VERSION 5.7 ;
  NOWIREEXTENSIONATPIN ON ;
  DIVIDERCHAR "/" ;
  BUSBITCHARS "[]" ;
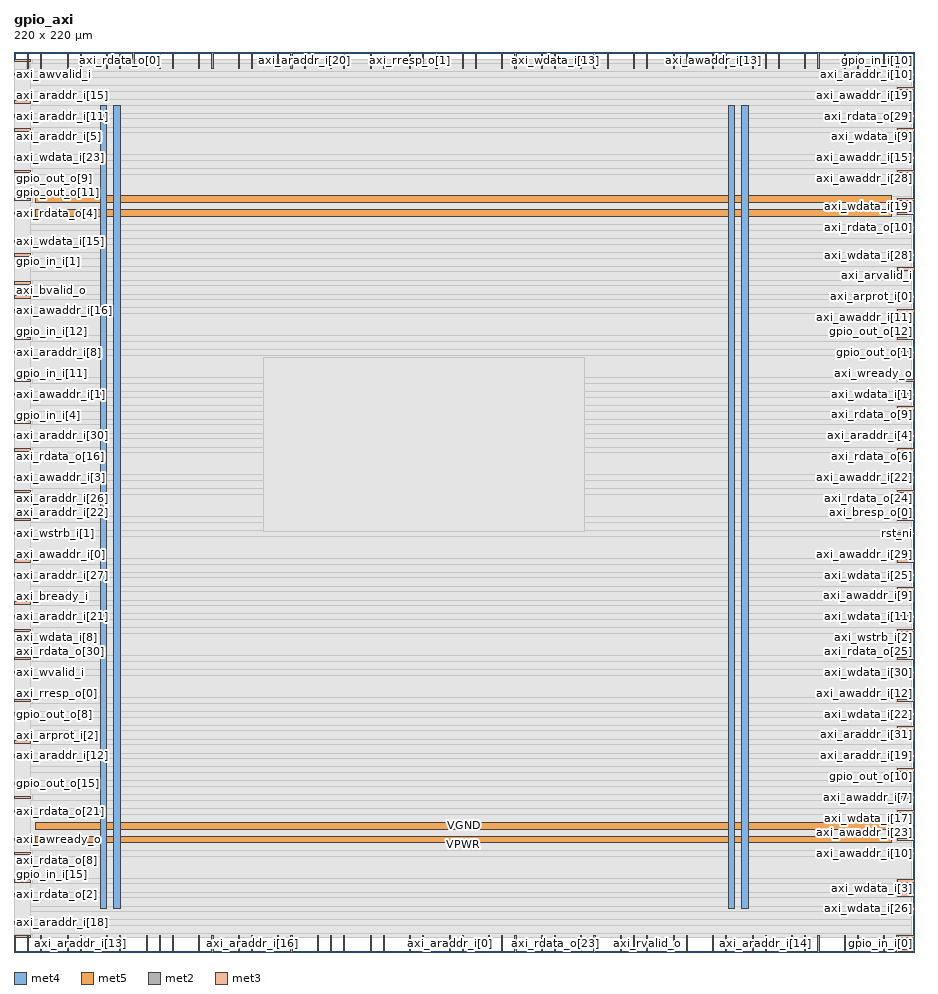
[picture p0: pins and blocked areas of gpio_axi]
MACRO gpio_axi
  CLASS BLOCK ;
  FOREIGN gpio_axi ;
  ORIGIN 0.000 0.000 ;
  SIZE 220.000 BY 220.000 ;
  PIN VGND
    DIRECTION INOUT ;
    USE GROUND ;
    PORT
      LAYER met4 ;
        RECT 24.340 10.640 25.940 206.960 ;
    END
    PORT
      LAYER met4 ;
        RECT 177.940 10.640 179.540 206.960 ;
    END
    PORT
      LAYER met5 ;
        RECT 5.280 30.030 214.600 31.630 ;
    END
    PORT
      LAYER met5 ;
        RECT 5.280 183.210 214.600 184.810 ;
    END
  END VGND
  PIN VPWR
    DIRECTION INOUT ;
    USE POWER ;
    PORT
      LAYER met4 ;
        RECT 21.040 10.640 22.640 206.960 ;
    END
    PORT
      LAYER met4 ;
        RECT 174.640 10.640 176.240 206.960 ;
    END
    PORT
      LAYER met5 ;
        RECT 5.280 26.730 214.600 28.330 ;
    END
    PORT
      LAYER met5 ;
        RECT 5.280 179.910 214.600 181.510 ;
    END
  END VPWR
  PIN axi_araddr_i[0]
    DIRECTION INPUT ;
    USE SIGNAL ;
    PORT
      LAYER met2 ;
        RECT 106.350 0.000 106.630 4.000 ;
    END
  END axi_araddr_i[0]
  PIN axi_araddr_i[10]
    DIRECTION INPUT ;
    USE SIGNAL ;
    PORT
      LAYER met3 ;
        RECT 216.000 214.240 220.000 214.840 ;
    END
  END axi_araddr_i[10]
  PIN axi_araddr_i[11]
    DIRECTION INPUT ;
    USE SIGNAL ;
    PORT
      LAYER met3 ;
        RECT 0.000 204.040 4.000 204.640 ;
    END
  END axi_araddr_i[11]
  PIN axi_araddr_i[12]
    DIRECTION INPUT ;
    USE SIGNAL ;
    PORT
      LAYER met3 ;
        RECT 0.000 47.640 4.000 48.240 ;
    END
  END axi_araddr_i[12]
  PIN axi_araddr_i[13]
    DIRECTION INPUT ;
    USE SIGNAL ;
    PORT
      LAYER met2 ;
        RECT 16.190 0.000 16.470 4.000 ;
    END
  END axi_araddr_i[13]
  PIN axi_araddr_i[14]
    DIRECTION INPUT ;
    USE SIGNAL ;
    PORT
      LAYER met2 ;
        RECT 183.630 0.000 183.910 4.000 ;
    END
  END axi_araddr_i[14]
  PIN axi_araddr_i[15]
    DIRECTION INPUT ;
    USE SIGNAL ;
    PORT
      LAYER met3 ;
        RECT 0.000 207.440 4.000 208.040 ;
    END
  END axi_araddr_i[15]
  PIN axi_araddr_i[16]
    DIRECTION INPUT ;
    USE SIGNAL ;
    PORT
      LAYER met2 ;
        RECT 58.050 0.000 58.330 4.000 ;
    END
  END axi_araddr_i[16]
  PIN axi_araddr_i[17]
    DIRECTION INPUT ;
    USE SIGNAL ;
    PORT
      LAYER met3 ;
        RECT 216.000 17.040 220.000 17.640 ;
    END
  END axi_araddr_i[17]
  PIN axi_araddr_i[18]
    DIRECTION INPUT ;
    USE SIGNAL ;
    PORT
      LAYER met3 ;
        RECT 0.000 6.840 4.000 7.440 ;
    END
  END axi_araddr_i[18]
  PIN axi_araddr_i[19]
    DIRECTION INPUT ;
    USE SIGNAL ;
    PORT
      LAYER met3 ;
        RECT 216.000 47.640 220.000 48.240 ;
    END
  END axi_araddr_i[19]
  PIN axi_araddr_i[1]
    DIRECTION INPUT ;
    USE SIGNAL ;
    PORT
      LAYER met2 ;
        RECT 193.290 0.000 193.570 4.000 ;
    END
  END axi_araddr_i[1]
  PIN axi_araddr_i[20]
    DIRECTION INPUT ;
    USE SIGNAL ;
    PORT
      LAYER met2 ;
        RECT 70.930 216.000 71.210 220.000 ;
    END
  END axi_araddr_i[20]
  PIN axi_araddr_i[21]
    DIRECTION INPUT ;
    USE SIGNAL ;
    PORT
      LAYER met3 ;
        RECT 0.000 81.640 4.000 82.240 ;
    END
  END axi_araddr_i[21]
  PIN axi_araddr_i[22]
    DIRECTION INPUT ;
    USE SIGNAL ;
    PORT
      LAYER met3 ;
        RECT 0.000 105.440 4.000 106.040 ;
    END
  END axi_araddr_i[22]
  PIN axi_araddr_i[23]
    DIRECTION INPUT ;
    USE SIGNAL ;
    PORT
      LAYER met2 ;
        RECT 122.450 216.000 122.730 220.000 ;
    END
  END axi_araddr_i[23]
  PIN axi_araddr_i[24]
    DIRECTION INPUT ;
    USE SIGNAL ;
    PORT
      LAYER met2 ;
        RECT 48.390 0.000 48.670 4.000 ;
    END
  END axi_araddr_i[24]
  PIN axi_araddr_i[25]
    DIRECTION INPUT ;
    USE SIGNAL ;
    PORT
      LAYER met2 ;
        RECT 64.490 216.000 64.770 220.000 ;
    END
  END axi_araddr_i[25]
  PIN axi_araddr_i[26]
    DIRECTION INPUT ;
    USE SIGNAL ;
    PORT
      LAYER met3 ;
        RECT 0.000 112.240 4.000 112.840 ;
    END
  END axi_araddr_i[26]
  PIN axi_araddr_i[27]
    DIRECTION INPUT ;
    USE SIGNAL ;
    PORT
      LAYER met3 ;
        RECT 0.000 91.840 4.000 92.440 ;
    END
  END axi_araddr_i[27]
  PIN axi_araddr_i[28]
    DIRECTION INPUT ;
    USE SIGNAL ;
    PORT
      LAYER met2 ;
        RECT 141.770 0.000 142.050 4.000 ;
    END
  END axi_araddr_i[28]
  PIN axi_araddr_i[29]
    DIRECTION INPUT ;
    USE SIGNAL ;
    PORT
      LAYER met2 ;
        RECT 196.510 216.000 196.790 220.000 ;
    END
  END axi_araddr_i[29]
  PIN axi_araddr_i[2]
    DIRECTION INPUT ;
    USE SIGNAL ;
    ANTENNAGATEAREA 0.196500 ;
    PORT
      LAYER met2 ;
        RECT 119.230 216.000 119.510 220.000 ;
    END
  END axi_araddr_i[2]
  PIN axi_araddr_i[30]
    DIRECTION INPUT ;
    USE SIGNAL ;
    PORT
      LAYER met3 ;
        RECT 0.000 125.840 4.000 126.440 ;
    END
  END axi_araddr_i[30]
  PIN axi_araddr_i[31]
    DIRECTION INPUT ;
    USE SIGNAL ;
    PORT
      LAYER met3 ;
        RECT 216.000 54.440 220.000 55.040 ;
    END
  END axi_araddr_i[31]
  PIN axi_araddr_i[3]
    DIRECTION INPUT ;
    USE SIGNAL ;
    ANTENNAGATEAREA 0.213000 ;
    PORT
      LAYER met2 ;
        RECT 45.170 216.000 45.450 220.000 ;
    END
  END axi_araddr_i[3]
  PIN axi_araddr_i[4]
    DIRECTION INPUT ;
    USE SIGNAL ;
    PORT
      LAYER met3 ;
        RECT 216.000 125.840 220.000 126.440 ;
    END
  END axi_araddr_i[4]
  PIN axi_araddr_i[5]
    DIRECTION INPUT ;
    USE SIGNAL ;
    PORT
      LAYER met3 ;
        RECT 0.000 200.640 4.000 201.240 ;
    END
  END axi_araddr_i[5]
  PIN axi_araddr_i[6]
    DIRECTION INPUT ;
    USE SIGNAL ;
    PORT
      LAYER met2 ;
        RECT 193.290 216.000 193.570 220.000 ;
    END
  END axi_araddr_i[6]
  PIN axi_araddr_i[7]
    DIRECTION INPUT ;
    USE SIGNAL ;
    PORT
      LAYER met2 ;
        RECT 138.550 216.000 138.830 220.000 ;
    END
  END axi_araddr_i[7]
  PIN axi_araddr_i[8]
    DIRECTION INPUT ;
    USE SIGNAL ;
    PORT
      LAYER met3 ;
        RECT 0.000 146.240 4.000 146.840 ;
    END
  END axi_araddr_i[8]
  PIN axi_araddr_i[9]
    DIRECTION INPUT ;
    USE SIGNAL ;
    PORT
      LAYER met3 ;
        RECT 216.000 183.640 220.000 184.240 ;
    END
  END axi_araddr_i[9]
  PIN axi_arprot_i[0]
    DIRECTION INPUT ;
    USE SIGNAL ;
    PORT
      LAYER met3 ;
        RECT 216.000 159.840 220.000 160.440 ;
    END
  END axi_arprot_i[0]
  PIN axi_arprot_i[1]
    DIRECTION INPUT ;
    USE SIGNAL ;
    PORT
      LAYER met2 ;
        RECT 206.170 0.000 206.450 4.000 ;
    END
  END axi_arprot_i[1]
  PIN axi_arprot_i[2]
    DIRECTION INPUT ;
    USE SIGNAL ;
    PORT
      LAYER met3 ;
        RECT 0.000 51.040 4.000 51.640 ;
    END
  END axi_arprot_i[2]
  PIN axi_arready_o
    DIRECTION OUTPUT TRISTATE ;
    USE SIGNAL ;
    ANTENNADIFFAREA 0.795200 ;
    PORT
      LAYER met2 ;
        RECT 67.710 216.000 67.990 220.000 ;
    END
  END axi_arready_o
  PIN axi_arvalid_i
    DIRECTION INPUT ;
    USE SIGNAL ;
    ANTENNAGATEAREA 0.196500 ;
    PORT
      LAYER met3 ;
        RECT 216.000 166.640 220.000 167.240 ;
    END
  END axi_arvalid_i
  PIN axi_awaddr_i[0]
    DIRECTION INPUT ;
    USE SIGNAL ;
    PORT
      LAYER met3 ;
        RECT 0.000 95.240 4.000 95.840 ;
    END
  END axi_awaddr_i[0]
  PIN axi_awaddr_i[10]
    DIRECTION INPUT ;
    USE SIGNAL ;
    PORT
      LAYER met3 ;
        RECT 216.000 23.840 220.000 24.440 ;
    END
  END axi_awaddr_i[10]
  PIN axi_awaddr_i[11]
    DIRECTION INPUT ;
    USE SIGNAL ;
    PORT
      LAYER met3 ;
        RECT 216.000 156.440 220.000 157.040 ;
    END
  END axi_awaddr_i[11]
  PIN axi_awaddr_i[12]
    DIRECTION INPUT ;
    USE SIGNAL ;
    PORT
      LAYER met3 ;
        RECT 216.000 61.240 220.000 61.840 ;
    END
  END axi_awaddr_i[12]
  PIN axi_awaddr_i[13]
    DIRECTION INPUT ;
    USE SIGNAL ;
    PORT
      LAYER met2 ;
        RECT 170.750 216.000 171.030 220.000 ;
    END
  END axi_awaddr_i[13]
  PIN axi_awaddr_i[14]
    DIRECTION INPUT ;
    USE SIGNAL ;
    PORT
      LAYER met2 ;
        RECT 164.310 216.000 164.590 220.000 ;
    END
  END axi_awaddr_i[14]
  PIN axi_awaddr_i[15]
    DIRECTION INPUT ;
    USE SIGNAL ;
    PORT
      LAYER met3 ;
        RECT 216.000 193.840 220.000 194.440 ;
    END
  END axi_awaddr_i[15]
  PIN axi_awaddr_i[16]
    DIRECTION INPUT ;
    USE SIGNAL ;
    PORT
      LAYER met3 ;
        RECT 0.000 156.440 4.000 157.040 ;
    END
  END axi_awaddr_i[16]
  PIN axi_awaddr_i[17]
    DIRECTION INPUT ;
    USE SIGNAL ;
    PORT
      LAYER met2 ;
        RECT 48.390 216.000 48.670 220.000 ;
    END
  END axi_awaddr_i[17]
  PIN axi_awaddr_i[18]
    DIRECTION INPUT ;
    USE SIGNAL ;
    PORT
      LAYER met2 ;
        RECT 87.030 0.000 87.310 4.000 ;
    END
  END axi_awaddr_i[18]
  PIN axi_awaddr_i[19]
    DIRECTION INPUT ;
    USE SIGNAL ;
    PORT
      LAYER met3 ;
        RECT 216.000 210.840 220.000 211.440 ;
    END
  END axi_awaddr_i[19]
  PIN axi_awaddr_i[1]
    DIRECTION INPUT ;
    USE SIGNAL ;
    PORT
      LAYER met3 ;
        RECT 0.000 136.040 4.000 136.640 ;
    END
  END axi_awaddr_i[1]
  PIN axi_awaddr_i[20]
    DIRECTION INPUT ;
    USE SIGNAL ;
    PORT
      LAYER met3 ;
        RECT 0.000 3.440 4.000 4.040 ;
    END
  END axi_awaddr_i[20]
  PIN axi_awaddr_i[21]
    DIRECTION INPUT ;
    USE SIGNAL ;
    PORT
      LAYER met2 ;
        RECT 35.510 0.000 35.790 4.000 ;
    END
  END axi_awaddr_i[21]
  PIN axi_awaddr_i[22]
    DIRECTION INPUT ;
    USE SIGNAL ;
    PORT
      LAYER met3 ;
        RECT 216.000 115.640 220.000 116.240 ;
    END
  END axi_awaddr_i[22]
  PIN axi_awaddr_i[23]
    DIRECTION INPUT ;
    USE SIGNAL ;
    PORT
      LAYER met3 ;
        RECT 216.000 27.240 220.000 27.840 ;
    END
  END axi_awaddr_i[23]
  PIN axi_awaddr_i[24]
    DIRECTION INPUT ;
    USE SIGNAL ;
    PORT
      LAYER met2 ;
        RECT 90.250 216.000 90.530 220.000 ;
    END
  END axi_awaddr_i[24]
  PIN axi_awaddr_i[25]
    DIRECTION INPUT ;
    USE SIGNAL ;
    PORT
      LAYER met2 ;
        RECT 67.710 0.000 67.990 4.000 ;
    END
  END axi_awaddr_i[25]
  PIN axi_awaddr_i[26]
    DIRECTION INPUT ;
    USE SIGNAL ;
    PORT
      LAYER met2 ;
        RECT 138.550 0.000 138.830 4.000 ;
    END
  END axi_awaddr_i[26]
  PIN axi_awaddr_i[27]
    DIRECTION INPUT ;
    USE SIGNAL ;
    PORT
      LAYER met2 ;
        RECT 3.310 216.000 3.590 220.000 ;
    END
  END axi_awaddr_i[27]
  PIN axi_awaddr_i[28]
    DIRECTION INPUT ;
    USE SIGNAL ;
    PORT
      LAYER met3 ;
        RECT 216.000 190.440 220.000 191.040 ;
    END
  END axi_awaddr_i[28]
  PIN axi_awaddr_i[29]
    DIRECTION INPUT ;
    USE SIGNAL ;
    PORT
      LAYER met3 ;
        RECT 216.000 95.240 220.000 95.840 ;
    END
  END axi_awaddr_i[29]
  PIN axi_awaddr_i[2]
    DIRECTION INPUT ;
    USE SIGNAL ;
    ANTENNAGATEAREA 0.196500 ;
    PORT
      LAYER met2 ;
        RECT 80.590 216.000 80.870 220.000 ;
    END
  END axi_awaddr_i[2]
  PIN axi_awaddr_i[30]
    DIRECTION INPUT ;
    USE SIGNAL ;
    PORT
      LAYER met2 ;
        RECT 161.090 0.000 161.370 4.000 ;
    END
  END axi_awaddr_i[30]
  PIN axi_awaddr_i[31]
    DIRECTION INPUT ;
    USE SIGNAL ;
    PORT
      LAYER met2 ;
        RECT 173.970 216.000 174.250 220.000 ;
    END
  END axi_awaddr_i[31]
  PIN axi_awaddr_i[3]
    DIRECTION INPUT ;
    USE SIGNAL ;
    ANTENNAGATEAREA 0.196500 ;
    PORT
      LAYER met3 ;
        RECT 0.000 115.640 4.000 116.240 ;
    END
  END axi_awaddr_i[3]
  PIN axi_awaddr_i[4]
    DIRECTION INPUT ;
    USE SIGNAL ;
    PORT
      LAYER met2 ;
        RECT 206.170 216.000 206.450 220.000 ;
    END
  END axi_awaddr_i[4]
  PIN axi_awaddr_i[5]
    DIRECTION INPUT ;
    USE SIGNAL ;
    PORT
      LAYER met3 ;
        RECT 216.000 0.040 220.000 0.640 ;
    END
  END axi_awaddr_i[5]
  PIN axi_awaddr_i[6]
    DIRECTION INPUT ;
    USE SIGNAL ;
    PORT
      LAYER met2 ;
        RECT 202.950 216.000 203.230 220.000 ;
    END
  END axi_awaddr_i[6]
  PIN axi_awaddr_i[7]
    DIRECTION INPUT ;
    USE SIGNAL ;
    PORT
      LAYER met3 ;
        RECT 216.000 37.440 220.000 38.040 ;
    END
  END axi_awaddr_i[7]
  PIN axi_awaddr_i[8]
    DIRECTION INPUT ;
    USE SIGNAL ;
    PORT
      LAYER met2 ;
        RECT 99.910 0.000 100.190 4.000 ;
    END
  END axi_awaddr_i[8]
  PIN axi_awaddr_i[9]
    DIRECTION INPUT ;
    USE SIGNAL ;
    PORT
      LAYER met3 ;
        RECT 216.000 88.440 220.000 89.040 ;
    END
  END axi_awaddr_i[9]
  PIN axi_awprot_i[0]
    DIRECTION INPUT ;
    USE SIGNAL ;
    PORT
      LAYER met2 ;
        RECT 183.630 216.000 183.910 220.000 ;
    END
  END axi_awprot_i[0]
  PIN axi_awprot_i[1]
    DIRECTION INPUT ;
    USE SIGNAL ;
    PORT
      LAYER met2 ;
        RECT 164.310 0.000 164.590 4.000 ;
    END
  END axi_awprot_i[1]
  PIN axi_awprot_i[2]
    DIRECTION INPUT ;
    USE SIGNAL ;
    PORT
      LAYER met2 ;
        RECT 64.490 0.000 64.770 4.000 ;
    END
  END axi_awprot_i[2]
  PIN axi_awready_o
    DIRECTION OUTPUT TRISTATE ;
    USE SIGNAL ;
    ANTENNADIFFAREA 0.795200 ;
    PORT
      LAYER met3 ;
        RECT 0.000 27.240 4.000 27.840 ;
    END
  END axi_awready_o
  PIN axi_awvalid_i
    DIRECTION INPUT ;
    USE SIGNAL ;
    ANTENNAGATEAREA 0.196500 ;
    PORT
      LAYER met3 ;
        RECT 0.000 214.240 4.000 214.840 ;
    END
  END axi_awvalid_i
  PIN axi_bready_i
    DIRECTION INPUT ;
    USE SIGNAL ;
    ANTENNAGATEAREA 0.196500 ;
    PORT
      LAYER met3 ;
        RECT 0.000 85.040 4.000 85.640 ;
    END
  END axi_bready_i
  PIN axi_bresp_o[0]
    DIRECTION OUTPUT TRISTATE ;
    USE SIGNAL ;
    PORT
      LAYER met3 ;
        RECT 216.000 105.440 220.000 106.040 ;
    END
  END axi_bresp_o[0]
  PIN axi_bresp_o[1]
    DIRECTION OUTPUT TRISTATE ;
    USE SIGNAL ;
    PORT
      LAYER met2 ;
        RECT 87.030 216.000 87.310 220.000 ;
    END
  END axi_bresp_o[1]
  PIN axi_bvalid_o
    DIRECTION OUTPUT TRISTATE ;
    USE SIGNAL ;
    ANTENNADIFFAREA 0.795200 ;
    PORT
      LAYER met3 ;
        RECT 0.000 159.840 4.000 160.440 ;
    END
  END axi_bvalid_o
  PIN axi_rdata_o[0]
    DIRECTION OUTPUT TRISTATE ;
    USE SIGNAL ;
    ANTENNADIFFAREA 0.795200 ;
    PORT
      LAYER met2 ;
        RECT 25.850 216.000 26.130 220.000 ;
    END
  END axi_rdata_o[0]
  PIN axi_rdata_o[10]
    DIRECTION OUTPUT TRISTATE ;
    USE SIGNAL ;
    ANTENNADIFFAREA 0.445500 ;
    PORT
      LAYER met3 ;
        RECT 216.000 176.840 220.000 177.440 ;
    END
  END axi_rdata_o[10]
  PIN axi_rdata_o[11]
    DIRECTION OUTPUT TRISTATE ;
    USE SIGNAL ;
    ANTENNADIFFAREA 0.795200 ;
    PORT
      LAYER met2 ;
        RECT 12.970 216.000 13.250 220.000 ;
    END
  END axi_rdata_o[11]
  PIN axi_rdata_o[12]
    DIRECTION OUTPUT TRISTATE ;
    USE SIGNAL ;
    ANTENNADIFFAREA 0.795200 ;
    PORT
      LAYER met2 ;
        RECT 54.830 216.000 55.110 220.000 ;
    END
  END axi_rdata_o[12]
  PIN axi_rdata_o[13]
    DIRECTION OUTPUT TRISTATE ;
    USE SIGNAL ;
    ANTENNADIFFAREA 0.795200 ;
    PORT
      LAYER met2 ;
        RECT 170.750 0.000 171.030 4.000 ;
    END
  END axi_rdata_o[13]
  PIN axi_rdata_o[14]
    DIRECTION OUTPUT TRISTATE ;
    USE SIGNAL ;
    ANTENNADIFFAREA 0.795200 ;
    PORT
      LAYER met2 ;
        RECT 112.790 216.000 113.070 220.000 ;
    END
  END axi_rdata_o[14]
  PIN axi_rdata_o[15]
    DIRECTION OUTPUT TRISTATE ;
    USE SIGNAL ;
    ANTENNADIFFAREA 0.795200 ;
    PORT
      LAYER met2 ;
        RECT 215.830 216.000 216.110 220.000 ;
    END
  END axi_rdata_o[15]
  PIN axi_rdata_o[16]
    DIRECTION OUTPUT TRISTATE ;
    USE SIGNAL ;
    PORT
      LAYER met3 ;
        RECT 0.000 122.440 4.000 123.040 ;
    END
  END axi_rdata_o[16]
  PIN axi_rdata_o[17]
    DIRECTION OUTPUT TRISTATE ;
    USE SIGNAL ;
    PORT
      LAYER met2 ;
        RECT 6.530 0.000 6.810 4.000 ;
    END
  END axi_rdata_o[17]
  PIN axi_rdata_o[18]
    DIRECTION OUTPUT TRISTATE ;
    USE SIGNAL ;
    PORT
      LAYER met2 ;
        RECT 74.150 0.000 74.430 4.000 ;
    END
  END axi_rdata_o[18]
  PIN axi_rdata_o[19]
    DIRECTION OUTPUT TRISTATE ;
    USE SIGNAL ;
    PORT
      LAYER met2 ;
        RECT 38.730 216.000 39.010 220.000 ;
    END
  END axi_rdata_o[19]
  PIN axi_rdata_o[1]
    DIRECTION OUTPUT TRISTATE ;
    USE SIGNAL ;
    ANTENNADIFFAREA 0.795200 ;
    PORT
      LAYER met3 ;
        RECT 216.000 3.440 220.000 4.040 ;
    END
  END axi_rdata_o[1]
  PIN axi_rdata_o[20]
    DIRECTION OUTPUT TRISTATE ;
    USE SIGNAL ;
    PORT
      LAYER met2 ;
        RECT 80.590 0.000 80.870 4.000 ;
    END
  END axi_rdata_o[20]
  PIN axi_rdata_o[21]
    DIRECTION OUTPUT TRISTATE ;
    USE SIGNAL ;
    PORT
      LAYER met3 ;
        RECT 0.000 34.040 4.000 34.640 ;
    END
  END axi_rdata_o[21]
  PIN axi_rdata_o[22]
    DIRECTION OUTPUT TRISTATE ;
    USE SIGNAL ;
    PORT
      LAYER met2 ;
        RECT 180.410 0.000 180.690 4.000 ;
    END
  END axi_rdata_o[22]
  PIN axi_rdata_o[23]
    DIRECTION OUTPUT TRISTATE ;
    USE SIGNAL ;
    PORT
      LAYER met2 ;
        RECT 132.110 0.000 132.390 4.000 ;
    END
  END axi_rdata_o[23]
  PIN axi_rdata_o[24]
    DIRECTION OUTPUT TRISTATE ;
    USE SIGNAL ;
    PORT
      LAYER met3 ;
        RECT 216.000 112.240 220.000 112.840 ;
    END
  END axi_rdata_o[24]
  PIN axi_rdata_o[25]
    DIRECTION OUTPUT TRISTATE ;
    USE SIGNAL ;
    PORT
      LAYER met3 ;
        RECT 216.000 71.440 220.000 72.040 ;
    END
  END axi_rdata_o[25]
  PIN axi_rdata_o[26]
    DIRECTION OUTPUT TRISTATE ;
    USE SIGNAL ;
    PORT
      LAYER met2 ;
        RECT 186.850 216.000 187.130 220.000 ;
    END
  END axi_rdata_o[26]
  PIN axi_rdata_o[27]
    DIRECTION OUTPUT TRISTATE ;
    USE SIGNAL ;
    PORT
      LAYER met2 ;
        RECT 141.770 216.000 142.050 220.000 ;
    END
  END axi_rdata_o[27]
  PIN axi_rdata_o[28]
    DIRECTION OUTPUT TRISTATE ;
    USE SIGNAL ;
    PORT
      LAYER met2 ;
        RECT 173.970 0.000 174.250 4.000 ;
    END
  END axi_rdata_o[28]
  PIN axi_rdata_o[29]
    DIRECTION OUTPUT TRISTATE ;
    USE SIGNAL ;
    PORT
      LAYER met3 ;
        RECT 216.000 204.040 220.000 204.640 ;
    END
  END axi_rdata_o[29]
  PIN axi_rdata_o[2]
    DIRECTION OUTPUT TRISTATE ;
    USE SIGNAL ;
    ANTENNADIFFAREA 0.795200 ;
    PORT
      LAYER met3 ;
        RECT 0.000 13.640 4.000 14.240 ;
    END
  END axi_rdata_o[2]
  PIN axi_rdata_o[30]
    DIRECTION OUTPUT TRISTATE ;
    USE SIGNAL ;
    PORT
      LAYER met3 ;
        RECT 0.000 71.440 4.000 72.040 ;
    END
  END axi_rdata_o[30]
  PIN axi_rdata_o[31]
    DIRECTION OUTPUT TRISTATE ;
    USE SIGNAL ;
    PORT
      LAYER met2 ;
        RECT 77.370 216.000 77.650 220.000 ;
    END
  END axi_rdata_o[31]
  PIN axi_rdata_o[3]
    DIRECTION OUTPUT TRISTATE ;
    USE SIGNAL ;
    ANTENNADIFFAREA 0.795200 ;
    PORT
      LAYER met2 ;
        RECT 6.530 216.000 6.810 220.000 ;
    END
  END axi_rdata_o[3]
  PIN axi_rdata_o[4]
    DIRECTION OUTPUT TRISTATE ;
    USE SIGNAL ;
    ANTENNADIFFAREA 0.795200 ;
    PORT
      LAYER met3 ;
        RECT 0.000 180.240 4.000 180.840 ;
    END
  END axi_rdata_o[4]
  PIN axi_rdata_o[5]
    DIRECTION OUTPUT TRISTATE ;
    USE SIGNAL ;
    ANTENNADIFFAREA 0.795200 ;
    PORT
      LAYER met2 ;
        RECT 22.630 216.000 22.910 220.000 ;
    END
  END axi_rdata_o[5]
  PIN axi_rdata_o[6]
    DIRECTION OUTPUT TRISTATE ;
    USE SIGNAL ;
    ANTENNADIFFAREA 0.445500 ;
    PORT
      LAYER met3 ;
        RECT 216.000 122.440 220.000 123.040 ;
    END
  END axi_rdata_o[6]
  PIN axi_rdata_o[7]
    DIRECTION OUTPUT TRISTATE ;
    USE SIGNAL ;
    ANTENNADIFFAREA 0.795200 ;
    PORT
      LAYER met2 ;
        RECT 215.830 0.000 216.110 4.000 ;
    END
  END axi_rdata_o[7]
  PIN axi_rdata_o[8]
    DIRECTION OUTPUT TRISTATE ;
    USE SIGNAL ;
    ANTENNADIFFAREA 0.795200 ;
    PORT
      LAYER met3 ;
        RECT 0.000 23.840 4.000 24.440 ;
    END
  END axi_rdata_o[8]
  PIN axi_rdata_o[9]
    DIRECTION OUTPUT TRISTATE ;
    USE SIGNAL ;
    ANTENNADIFFAREA 0.445500 ;
    PORT
      LAYER met3 ;
        RECT 216.000 132.640 220.000 133.240 ;
    END
  END axi_rdata_o[9]
  PIN axi_rready_i
    DIRECTION INPUT ;
    USE SIGNAL ;
    ANTENNAGATEAREA 0.196500 ;
    PORT
      LAYER met2 ;
        RECT 116.010 0.000 116.290 4.000 ;
    END
  END axi_rready_i
  PIN axi_rresp_o[0]
    DIRECTION OUTPUT TRISTATE ;
    USE SIGNAL ;
    PORT
      LAYER met3 ;
        RECT 0.000 61.240 4.000 61.840 ;
    END
  END axi_rresp_o[0]
  PIN axi_rresp_o[1]
    DIRECTION OUTPUT TRISTATE ;
    USE SIGNAL ;
    PORT
      LAYER met2 ;
        RECT 96.690 216.000 96.970 220.000 ;
    END
  END axi_rresp_o[1]
  PIN axi_rvalid_o
    DIRECTION OUTPUT TRISTATE ;
    USE SIGNAL ;
    ANTENNADIFFAREA 0.795200 ;
    PORT
      LAYER met2 ;
        RECT 154.650 0.000 154.930 4.000 ;
    END
  END axi_rvalid_o
  PIN axi_wdata_i[0]
    DIRECTION INPUT ;
    USE SIGNAL ;
    ANTENNAGATEAREA 0.196500 ;
    PORT
      LAYER met2 ;
        RECT 202.950 0.000 203.230 4.000 ;
    END
  END axi_wdata_i[0]
  PIN axi_wdata_i[10]
    DIRECTION INPUT ;
    USE SIGNAL ;
    ANTENNAGATEAREA 0.196500 ;
    PORT
      LAYER met3 ;
        RECT 0.000 163.240 4.000 163.840 ;
    END
  END axi_wdata_i[10]
  PIN axi_wdata_i[11]
    DIRECTION INPUT ;
    USE SIGNAL ;
    ANTENNAGATEAREA 0.126000 ;
    PORT
      LAYER met3 ;
        RECT 216.000 81.640 220.000 82.240 ;
    END
  END axi_wdata_i[11]
  PIN axi_wdata_i[12]
    DIRECTION INPUT ;
    USE SIGNAL ;
    ANTENNAGATEAREA 0.196500 ;
    PORT
      LAYER met2 ;
        RECT 99.910 216.000 100.190 220.000 ;
    END
  END axi_wdata_i[12]
  PIN axi_wdata_i[13]
    DIRECTION INPUT ;
    USE SIGNAL ;
    ANTENNAGATEAREA 0.196500 ;
    PORT
      LAYER met2 ;
        RECT 132.110 216.000 132.390 220.000 ;
    END
  END axi_wdata_i[13]
  PIN axi_wdata_i[14]
    DIRECTION INPUT ;
    USE SIGNAL ;
    ANTENNAGATEAREA 0.196500 ;
    PORT
      LAYER met2 ;
        RECT 128.890 216.000 129.170 220.000 ;
    END
  END axi_wdata_i[14]
  PIN axi_wdata_i[15]
    DIRECTION INPUT ;
    USE SIGNAL ;
    ANTENNAGATEAREA 0.196500 ;
    PORT
      LAYER met3 ;
        RECT 0.000 173.440 4.000 174.040 ;
    END
  END axi_wdata_i[15]
  PIN axi_wdata_i[16]
    DIRECTION INPUT ;
    USE SIGNAL ;
    PORT
      LAYER met2 ;
        RECT 32.290 0.000 32.570 4.000 ;
    END
  END axi_wdata_i[16]
  PIN axi_wdata_i[17]
    DIRECTION INPUT ;
    USE SIGNAL ;
    PORT
      LAYER met3 ;
        RECT 216.000 34.040 220.000 34.640 ;
    END
  END axi_wdata_i[17]
  PIN axi_wdata_i[18]
    DIRECTION INPUT ;
    USE SIGNAL ;
    PORT
      LAYER met2 ;
        RECT 96.690 0.000 96.970 4.000 ;
    END
  END axi_wdata_i[18]
  PIN axi_wdata_i[19]
    DIRECTION INPUT ;
    USE SIGNAL ;
    PORT
      LAYER met3 ;
        RECT 216.000 180.240 220.000 180.840 ;
    END
  END axi_wdata_i[19]
  PIN axi_wdata_i[1]
    DIRECTION INPUT ;
    USE SIGNAL ;
    ANTENNAGATEAREA 0.196500 ;
    PORT
      LAYER met3 ;
        RECT 216.000 136.040 220.000 136.640 ;
    END
  END axi_wdata_i[1]
  PIN axi_wdata_i[20]
    DIRECTION INPUT ;
    USE SIGNAL ;
    PORT
      LAYER met2 ;
        RECT 144.990 216.000 145.270 220.000 ;
    END
  END axi_wdata_i[20]
  PIN axi_wdata_i[21]
    DIRECTION INPUT ;
    USE SIGNAL ;
    PORT
      LAYER met2 ;
        RECT 22.630 0.000 22.910 4.000 ;
    END
  END axi_wdata_i[21]
  PIN axi_wdata_i[22]
    DIRECTION INPUT ;
    USE SIGNAL ;
    PORT
      LAYER met3 ;
        RECT 216.000 57.840 220.000 58.440 ;
    END
  END axi_wdata_i[22]
  PIN axi_wdata_i[23]
    DIRECTION INPUT ;
    USE SIGNAL ;
    PORT
      LAYER met3 ;
        RECT 0.000 193.840 4.000 194.440 ;
    END
  END axi_wdata_i[23]
  PIN axi_wdata_i[24]
    DIRECTION INPUT ;
    USE SIGNAL ;
    PORT
      LAYER met2 ;
        RECT 58.050 216.000 58.330 220.000 ;
    END
  END axi_wdata_i[24]
  PIN axi_wdata_i[25]
    DIRECTION INPUT ;
    USE SIGNAL ;
    PORT
      LAYER met3 ;
        RECT 216.000 91.840 220.000 92.440 ;
    END
  END axi_wdata_i[25]
  PIN axi_wdata_i[26]
    DIRECTION INPUT ;
    USE SIGNAL ;
    PORT
      LAYER met3 ;
        RECT 216.000 10.240 220.000 10.840 ;
    END
  END axi_wdata_i[26]
  PIN axi_wdata_i[27]
    DIRECTION INPUT ;
    USE SIGNAL ;
    PORT
      LAYER met2 ;
        RECT 119.230 0.000 119.510 4.000 ;
    END
  END axi_wdata_i[27]
  PIN axi_wdata_i[28]
    DIRECTION INPUT ;
    USE SIGNAL ;
    PORT
      LAYER met3 ;
        RECT 216.000 170.040 220.000 170.640 ;
    END
  END axi_wdata_i[28]
  PIN axi_wdata_i[29]
    DIRECTION INPUT ;
    USE SIGNAL ;
    PORT
      LAYER met3 ;
        RECT 0.000 37.440 4.000 38.040 ;
    END
  END axi_wdata_i[29]
  PIN axi_wdata_i[2]
    DIRECTION INPUT ;
    USE SIGNAL ;
    ANTENNAGATEAREA 0.196500 ;
    PORT
      LAYER met2 ;
        RECT 54.830 0.000 55.110 4.000 ;
    END
  END axi_wdata_i[2]
  PIN axi_wdata_i[30]
    DIRECTION INPUT ;
    USE SIGNAL ;
    PORT
      LAYER met3 ;
        RECT 216.000 68.040 220.000 68.640 ;
    END
  END axi_wdata_i[30]
  PIN axi_wdata_i[31]
    DIRECTION INPUT ;
    USE SIGNAL ;
    PORT
      LAYER met2 ;
        RECT 148.210 0.000 148.490 4.000 ;
    END
  END axi_wdata_i[31]
  PIN axi_wdata_i[3]
    DIRECTION INPUT ;
    USE SIGNAL ;
    ANTENNAGATEAREA 0.196500 ;
    PORT
      LAYER met3 ;
        RECT 216.000 13.640 220.000 14.240 ;
    END
  END axi_wdata_i[3]
  PIN axi_wdata_i[4]
    DIRECTION INPUT ;
    USE SIGNAL ;
    ANTENNAGATEAREA 0.196500 ;
    PORT
      LAYER met2 ;
        RECT 16.190 216.000 16.470 220.000 ;
    END
  END axi_wdata_i[4]
  PIN axi_wdata_i[5]
    DIRECTION INPUT ;
    USE SIGNAL ;
    ANTENNAGATEAREA 0.126000 ;
    PORT
      LAYER met2 ;
        RECT 190.070 0.000 190.350 4.000 ;
    END
  END axi_wdata_i[5]
  PIN axi_wdata_i[6]
    DIRECTION INPUT ;
    USE SIGNAL ;
    ANTENNAGATEAREA 0.196500 ;
    PORT
      LAYER met2 ;
        RECT 25.850 0.000 26.130 4.000 ;
    END
  END axi_wdata_i[6]
  PIN axi_wdata_i[7]
    DIRECTION INPUT ;
    USE SIGNAL ;
    ANTENNAGATEAREA 0.196500 ;
    PORT
      LAYER met2 ;
        RECT 90.250 0.000 90.530 4.000 ;
    END
  END axi_wdata_i[7]
  PIN axi_wdata_i[8]
    DIRECTION INPUT ;
    USE SIGNAL ;
    ANTENNAGATEAREA 0.196500 ;
    PORT
      LAYER met3 ;
        RECT 0.000 78.240 4.000 78.840 ;
    END
  END axi_wdata_i[8]
  PIN axi_wdata_i[9]
    DIRECTION INPUT ;
    USE SIGNAL ;
    ANTENNAGATEAREA 0.196500 ;
    PORT
      LAYER met3 ;
        RECT 216.000 200.640 220.000 201.240 ;
    END
  END axi_wdata_i[9]
  PIN axi_wready_o
    DIRECTION OUTPUT TRISTATE ;
    USE SIGNAL ;
    ANTENNADIFFAREA 0.445500 ;
    PORT
      LAYER met3 ;
        RECT 216.000 139.440 220.000 140.040 ;
    END
  END axi_wready_o
  PIN axi_wstrb_i[0]
    DIRECTION INPUT ;
    USE SIGNAL ;
    PORT
      LAYER met2 ;
        RECT 196.510 0.000 196.790 4.000 ;
    END
  END axi_wstrb_i[0]
  PIN axi_wstrb_i[1]
    DIRECTION INPUT ;
    USE SIGNAL ;
    PORT
      LAYER met3 ;
        RECT 0.000 102.040 4.000 102.640 ;
    END
  END axi_wstrb_i[1]
  PIN axi_wstrb_i[2]
    DIRECTION INPUT ;
    USE SIGNAL ;
    PORT
      LAYER met3 ;
        RECT 216.000 78.240 220.000 78.840 ;
    END
  END axi_wstrb_i[2]
  PIN axi_wstrb_i[3]
    DIRECTION INPUT ;
    USE SIGNAL ;
    PORT
      LAYER met2 ;
        RECT 3.310 0.000 3.590 4.000 ;
    END
  END axi_wstrb_i[3]
  PIN axi_wvalid_i
    DIRECTION INPUT ;
    USE SIGNAL ;
    ANTENNAGATEAREA 0.196500 ;
    PORT
      LAYER met3 ;
        RECT 0.000 68.040 4.000 68.640 ;
    END
  END axi_wvalid_i
  PIN clk_i
    DIRECTION INPUT ;
    USE SIGNAL ;
    ANTENNAGATEAREA 0.852000 ;
    PORT
      LAYER met2 ;
        RECT 219.050 216.000 219.330 220.000 ;
    END
  END clk_i
  PIN gpio_in_i[0]
    DIRECTION INPUT ;
    USE SIGNAL ;
    ANTENNAGATEAREA 0.213000 ;
    PORT
      LAYER met2 ;
        RECT 212.610 0.000 212.890 4.000 ;
    END
  END gpio_in_i[0]
  PIN gpio_in_i[10]
    DIRECTION INPUT ;
    USE SIGNAL ;
    ANTENNAGATEAREA 0.196500 ;
    PORT
      LAYER met2 ;
        RECT 212.610 216.000 212.890 220.000 ;
    END
  END gpio_in_i[10]
  PIN gpio_in_i[11]
    DIRECTION INPUT ;
    USE SIGNAL ;
    ANTENNAGATEAREA 0.196500 ;
    PORT
      LAYER met3 ;
        RECT 0.000 139.440 4.000 140.040 ;
    END
  END gpio_in_i[11]
  PIN gpio_in_i[12]
    DIRECTION INPUT ;
    USE SIGNAL ;
    ANTENNAGATEAREA 0.196500 ;
    PORT
      LAYER met3 ;
        RECT 0.000 149.640 4.000 150.240 ;
    END
  END gpio_in_i[12]
  PIN gpio_in_i[13]
    DIRECTION INPUT ;
    USE SIGNAL ;
    ANTENNAGATEAREA 0.196500 ;
    PORT
      LAYER met2 ;
        RECT 128.890 0.000 129.170 4.000 ;
    END
  END gpio_in_i[13]
  PIN gpio_in_i[14]
    DIRECTION INPUT ;
    USE SIGNAL ;
    ANTENNAGATEAREA 0.213000 ;
    PORT
      LAYER met2 ;
        RECT 0.090 0.000 0.370 4.000 ;
    END
  END gpio_in_i[14]
  PIN gpio_in_i[15]
    DIRECTION INPUT ;
    USE SIGNAL ;
    ANTENNAGATEAREA 0.126000 ;
    PORT
      LAYER met3 ;
        RECT 0.000 17.040 4.000 17.640 ;
    END
  END gpio_in_i[15]
  PIN gpio_in_i[1]
    DIRECTION INPUT ;
    USE SIGNAL ;
    ANTENNAGATEAREA 0.213000 ;
    PORT
      LAYER met3 ;
        RECT 0.000 170.040 4.000 170.640 ;
    END
  END gpio_in_i[1]
  PIN gpio_in_i[2]
    DIRECTION INPUT ;
    USE SIGNAL ;
    ANTENNAGATEAREA 0.196500 ;
    PORT
      LAYER met2 ;
        RECT 29.070 216.000 29.350 220.000 ;
    END
  END gpio_in_i[2]
  PIN gpio_in_i[3]
    DIRECTION INPUT ;
    USE SIGNAL ;
    ANTENNAGATEAREA 0.196500 ;
    PORT
      LAYER met2 ;
        RECT 109.570 216.000 109.850 220.000 ;
    END
  END gpio_in_i[3]
  PIN gpio_in_i[4]
    DIRECTION INPUT ;
    USE SIGNAL ;
    ANTENNAGATEAREA 0.196500 ;
    PORT
      LAYER met3 ;
        RECT 0.000 129.240 4.000 129.840 ;
    END
  END gpio_in_i[4]
  PIN gpio_in_i[5]
    DIRECTION INPUT ;
    USE SIGNAL ;
    ANTENNAGATEAREA 0.126000 ;
    PORT
      LAYER met2 ;
        RECT 38.730 0.000 39.010 4.000 ;
    END
  END gpio_in_i[5]
  PIN gpio_in_i[6]
    DIRECTION INPUT ;
    USE SIGNAL ;
    ANTENNAGATEAREA 0.196500 ;
    PORT
      LAYER met2 ;
        RECT 12.970 0.000 13.250 4.000 ;
    END
  END gpio_in_i[6]
  PIN gpio_in_i[7]
    DIRECTION INPUT ;
    USE SIGNAL ;
    ANTENNAGATEAREA 0.196500 ;
    PORT
      LAYER met2 ;
        RECT 151.430 216.000 151.710 220.000 ;
    END
  END gpio_in_i[7]
  PIN gpio_in_i[8]
    DIRECTION INPUT ;
    USE SIGNAL ;
    ANTENNAGATEAREA 0.213000 ;
    PORT
      LAYER met2 ;
        RECT 103.130 216.000 103.410 220.000 ;
    END
  END gpio_in_i[8]
  PIN gpio_in_i[9]
    DIRECTION INPUT ;
    USE SIGNAL ;
    ANTENNAGATEAREA 0.196500 ;
    PORT
      LAYER met2 ;
        RECT 109.570 0.000 109.850 4.000 ;
    END
  END gpio_in_i[9]
  PIN gpio_out_o[0]
    DIRECTION OUTPUT TRISTATE ;
    USE SIGNAL ;
    ANTENNADIFFAREA 0.795200 ;
    PORT
      LAYER met2 ;
        RECT 180.410 216.000 180.690 220.000 ;
    END
  END gpio_out_o[0]
  PIN gpio_out_o[10]
    DIRECTION OUTPUT TRISTATE ;
    USE SIGNAL ;
    ANTENNADIFFAREA 0.445500 ;
    PORT
      LAYER met3 ;
        RECT 216.000 44.240 220.000 44.840 ;
    END
  END gpio_out_o[10]
  PIN gpio_out_o[11]
    DIRECTION OUTPUT TRISTATE ;
    USE SIGNAL ;
    ANTENNADIFFAREA 0.795200 ;
    PORT
      LAYER met3 ;
        RECT 0.000 183.640 4.000 184.240 ;
    END
  END gpio_out_o[11]
  PIN gpio_out_o[12]
    DIRECTION OUTPUT TRISTATE ;
    USE SIGNAL ;
    ANTENNADIFFAREA 0.445500 ;
    PORT
      LAYER met3 ;
        RECT 216.000 149.640 220.000 150.240 ;
    END
  END gpio_out_o[12]
  PIN gpio_out_o[13]
    DIRECTION OUTPUT TRISTATE ;
    USE SIGNAL ;
    ANTENNADIFFAREA 0.795200 ;
    PORT
      LAYER met2 ;
        RECT 45.170 0.000 45.450 4.000 ;
    END
  END gpio_out_o[13]
  PIN gpio_out_o[14]
    DIRECTION OUTPUT TRISTATE ;
    USE SIGNAL ;
    ANTENNADIFFAREA 0.795200 ;
    PORT
      LAYER met2 ;
        RECT 77.370 0.000 77.650 4.000 ;
    END
  END gpio_out_o[14]
  PIN gpio_out_o[15]
    DIRECTION OUTPUT TRISTATE ;
    USE SIGNAL ;
    ANTENNADIFFAREA 0.795200 ;
    PORT
      LAYER met3 ;
        RECT 0.000 40.840 4.000 41.440 ;
    END
  END gpio_out_o[15]
  PIN gpio_out_o[1]
    DIRECTION OUTPUT TRISTATE ;
    USE SIGNAL ;
    ANTENNADIFFAREA 0.445500 ;
    PORT
      LAYER met3 ;
        RECT 216.000 146.240 220.000 146.840 ;
    END
  END gpio_out_o[1]
  PIN gpio_out_o[2]
    DIRECTION OUTPUT TRISTATE ;
    USE SIGNAL ;
    ANTENNADIFFAREA 0.795200 ;
    PORT
      LAYER met2 ;
        RECT 122.450 0.000 122.730 4.000 ;
    END
  END gpio_out_o[2]
  PIN gpio_out_o[3]
    DIRECTION OUTPUT TRISTATE ;
    USE SIGNAL ;
    ANTENNADIFFAREA 0.795200 ;
    PORT
      LAYER met2 ;
        RECT 161.090 216.000 161.370 220.000 ;
    END
  END gpio_out_o[3]
  PIN gpio_out_o[4]
    DIRECTION OUTPUT TRISTATE ;
    USE SIGNAL ;
    ANTENNADIFFAREA 0.795200 ;
    PORT
      LAYER met2 ;
        RECT 154.650 216.000 154.930 220.000 ;
    END
  END gpio_out_o[4]
  PIN gpio_out_o[5]
    DIRECTION OUTPUT TRISTATE ;
    USE SIGNAL ;
    ANTENNADIFFAREA 0.795200 ;
    PORT
      LAYER met3 ;
        RECT 0.000 217.640 4.000 218.240 ;
    END
  END gpio_out_o[5]
  PIN gpio_out_o[6]
    DIRECTION OUTPUT TRISTATE ;
    USE SIGNAL ;
    ANTENNADIFFAREA 0.795200 ;
    PORT
      LAYER met2 ;
        RECT 35.510 216.000 35.790 220.000 ;
    END
  END gpio_out_o[6]
  PIN gpio_out_o[7]
    DIRECTION OUTPUT TRISTATE ;
    USE SIGNAL ;
    ANTENNADIFFAREA 0.795200 ;
    PORT
      LAYER met2 ;
        RECT 151.430 0.000 151.710 4.000 ;
    END
  END gpio_out_o[7]
  PIN gpio_out_o[8]
    DIRECTION OUTPUT TRISTATE ;
    USE SIGNAL ;
    ANTENNADIFFAREA 0.795200 ;
    PORT
      LAYER met3 ;
        RECT 0.000 57.840 4.000 58.440 ;
    END
  END gpio_out_o[8]
  PIN gpio_out_o[9]
    DIRECTION OUTPUT TRISTATE ;
    USE SIGNAL ;
    ANTENNADIFFAREA 0.795200 ;
    PORT
      LAYER met3 ;
        RECT 0.000 190.440 4.000 191.040 ;
    END
  END gpio_out_o[9]
  PIN rst_ni
    DIRECTION INPUT ;
    USE SIGNAL ;
    ANTENNAGATEAREA 0.196500 ;
    PORT
      LAYER met3 ;
        RECT 216.000 102.040 220.000 102.640 ;
    END
  END rst_ni
  OBS
      LAYER li1 ;
        RECT 5.520 10.795 214.360 206.805 ;
      LAYER met1 ;
        RECT 0.070 9.560 216.130 206.960 ;
      LAYER met2 ;
        RECT 0.100 215.720 3.030 218.125 ;
        RECT 3.870 215.720 6.250 218.125 ;
        RECT 7.090 215.720 12.690 218.125 ;
        RECT 13.530 215.720 15.910 218.125 ;
        RECT 16.750 215.720 22.350 218.125 ;
        RECT 23.190 215.720 25.570 218.125 ;
        RECT 26.410 215.720 28.790 218.125 ;
        RECT 29.630 215.720 35.230 218.125 ;
        RECT 36.070 215.720 38.450 218.125 ;
        RECT 39.290 215.720 44.890 218.125 ;
        RECT 45.730 215.720 48.110 218.125 ;
        RECT 48.950 215.720 54.550 218.125 ;
        RECT 55.390 215.720 57.770 218.125 ;
        RECT 58.610 215.720 64.210 218.125 ;
        RECT 65.050 215.720 67.430 218.125 ;
        RECT 68.270 215.720 70.650 218.125 ;
        RECT 71.490 215.720 77.090 218.125 ;
        RECT 77.930 215.720 80.310 218.125 ;
        RECT 81.150 215.720 86.750 218.125 ;
        RECT 87.590 215.720 89.970 218.125 ;
        RECT 90.810 215.720 96.410 218.125 ;
        RECT 97.250 215.720 99.630 218.125 ;
        RECT 100.470 215.720 102.850 218.125 ;
        RECT 103.690 215.720 109.290 218.125 ;
        RECT 110.130 215.720 112.510 218.125 ;
        RECT 113.350 215.720 118.950 218.125 ;
        RECT 119.790 215.720 122.170 218.125 ;
        RECT 123.010 215.720 128.610 218.125 ;
        RECT 129.450 215.720 131.830 218.125 ;
        RECT 132.670 215.720 138.270 218.125 ;
        RECT 139.110 215.720 141.490 218.125 ;
        RECT 142.330 215.720 144.710 218.125 ;
        RECT 145.550 215.720 151.150 218.125 ;
        RECT 151.990 215.720 154.370 218.125 ;
        RECT 155.210 215.720 160.810 218.125 ;
        RECT 161.650 215.720 164.030 218.125 ;
        RECT 164.870 215.720 170.470 218.125 ;
        RECT 171.310 215.720 173.690 218.125 ;
        RECT 174.530 215.720 180.130 218.125 ;
        RECT 180.970 215.720 183.350 218.125 ;
        RECT 184.190 215.720 186.570 218.125 ;
        RECT 187.410 215.720 193.010 218.125 ;
        RECT 193.850 215.720 196.230 218.125 ;
        RECT 197.070 215.720 202.670 218.125 ;
        RECT 203.510 215.720 205.890 218.125 ;
        RECT 206.730 215.720 212.330 218.125 ;
        RECT 213.170 215.720 215.550 218.125 ;
        RECT 216.390 215.720 218.770 218.125 ;
        RECT 0.100 4.280 219.330 215.720 ;
        RECT 0.650 3.555 3.030 4.280 ;
        RECT 3.870 3.555 6.250 4.280 ;
        RECT 7.090 3.555 12.690 4.280 ;
        RECT 13.530 3.555 15.910 4.280 ;
        RECT 16.750 3.555 22.350 4.280 ;
        RECT 23.190 3.555 25.570 4.280 ;
        RECT 26.410 3.555 32.010 4.280 ;
        RECT 32.850 3.555 35.230 4.280 ;
        RECT 36.070 3.555 38.450 4.280 ;
        RECT 39.290 3.555 44.890 4.280 ;
        RECT 45.730 3.555 48.110 4.280 ;
        RECT 48.950 3.555 54.550 4.280 ;
        RECT 55.390 3.555 57.770 4.280 ;
        RECT 58.610 3.555 64.210 4.280 ;
        RECT 65.050 3.555 67.430 4.280 ;
        RECT 68.270 3.555 73.870 4.280 ;
        RECT 74.710 3.555 77.090 4.280 ;
        RECT 77.930 3.555 80.310 4.280 ;
        RECT 81.150 3.555 86.750 4.280 ;
        RECT 87.590 3.555 89.970 4.280 ;
        RECT 90.810 3.555 96.410 4.280 ;
        RECT 97.250 3.555 99.630 4.280 ;
        RECT 100.470 3.555 106.070 4.280 ;
        RECT 106.910 3.555 109.290 4.280 ;
        RECT 110.130 3.555 115.730 4.280 ;
        RECT 116.570 3.555 118.950 4.280 ;
        RECT 119.790 3.555 122.170 4.280 ;
        RECT 123.010 3.555 128.610 4.280 ;
        RECT 129.450 3.555 131.830 4.280 ;
        RECT 132.670 3.555 138.270 4.280 ;
        RECT 139.110 3.555 141.490 4.280 ;
        RECT 142.330 3.555 147.930 4.280 ;
        RECT 148.770 3.555 151.150 4.280 ;
        RECT 151.990 3.555 154.370 4.280 ;
        RECT 155.210 3.555 160.810 4.280 ;
        RECT 161.650 3.555 164.030 4.280 ;
        RECT 164.870 3.555 170.470 4.280 ;
        RECT 171.310 3.555 173.690 4.280 ;
        RECT 174.530 3.555 180.130 4.280 ;
        RECT 180.970 3.555 183.350 4.280 ;
        RECT 184.190 3.555 189.790 4.280 ;
        RECT 190.630 3.555 193.010 4.280 ;
        RECT 193.850 3.555 196.230 4.280 ;
        RECT 197.070 3.555 202.670 4.280 ;
        RECT 203.510 3.555 205.890 4.280 ;
        RECT 206.730 3.555 212.330 4.280 ;
        RECT 213.170 3.555 215.550 4.280 ;
        RECT 216.390 3.555 219.330 4.280 ;
      LAYER met3 ;
        RECT 4.400 217.240 219.355 218.105 ;
        RECT 3.990 215.240 219.355 217.240 ;
        RECT 4.400 213.840 215.600 215.240 ;
        RECT 3.990 211.840 219.355 213.840 ;
        RECT 3.990 210.440 215.600 211.840 ;
        RECT 3.990 208.440 219.355 210.440 ;
        RECT 4.400 207.040 219.355 208.440 ;
        RECT 3.990 205.040 219.355 207.040 ;
        RECT 4.400 203.640 215.600 205.040 ;
        RECT 3.990 201.640 219.355 203.640 ;
        RECT 4.400 200.240 215.600 201.640 ;
        RECT 3.990 194.840 219.355 200.240 ;
        RECT 4.400 193.440 215.600 194.840 ;
        RECT 3.990 191.440 219.355 193.440 ;
        RECT 4.400 190.040 215.600 191.440 ;
        RECT 3.990 184.640 219.355 190.040 ;
        RECT 4.400 183.240 215.600 184.640 ;
        RECT 3.990 181.240 219.355 183.240 ;
        RECT 4.400 179.840 215.600 181.240 ;
        RECT 3.990 177.840 219.355 179.840 ;
        RECT 3.990 176.440 215.600 177.840 ;
        RECT 3.990 174.440 219.355 176.440 ;
        RECT 4.400 173.040 219.355 174.440 ;
        RECT 3.990 171.040 219.355 173.040 ;
        RECT 4.400 169.640 215.600 171.040 ;
        RECT 3.990 167.640 219.355 169.640 ;
        RECT 3.990 166.240 215.600 167.640 ;
        RECT 3.990 164.240 219.355 166.240 ;
        RECT 4.400 162.840 219.355 164.240 ;
        RECT 3.990 160.840 219.355 162.840 ;
        RECT 4.400 159.440 215.600 160.840 ;
        RECT 3.990 157.440 219.355 159.440 ;
        RECT 4.400 156.040 215.600 157.440 ;
        RECT 3.990 150.640 219.355 156.040 ;
        RECT 4.400 149.240 215.600 150.640 ;
        RECT 3.990 147.240 219.355 149.240 ;
        RECT 4.400 145.840 215.600 147.240 ;
        RECT 3.990 140.440 219.355 145.840 ;
        RECT 4.400 139.040 215.600 140.440 ;
        RECT 3.990 137.040 219.355 139.040 ;
        RECT 4.400 135.640 215.600 137.040 ;
        RECT 3.990 133.640 219.355 135.640 ;
        RECT 3.990 132.240 215.600 133.640 ;
        RECT 3.990 130.240 219.355 132.240 ;
        RECT 4.400 128.840 219.355 130.240 ;
        RECT 3.990 126.840 219.355 128.840 ;
        RECT 4.400 125.440 215.600 126.840 ;
        RECT 3.990 123.440 219.355 125.440 ;
        RECT 4.400 122.040 215.600 123.440 ;
        RECT 3.990 116.640 219.355 122.040 ;
        RECT 4.400 115.240 215.600 116.640 ;
        RECT 3.990 113.240 219.355 115.240 ;
        RECT 4.400 111.840 215.600 113.240 ;
        RECT 3.990 106.440 219.355 111.840 ;
        RECT 4.400 105.040 215.600 106.440 ;
        RECT 3.990 103.040 219.355 105.040 ;
        RECT 4.400 101.640 215.600 103.040 ;
        RECT 3.990 96.240 219.355 101.640 ;
        RECT 4.400 94.840 215.600 96.240 ;
        RECT 3.990 92.840 219.355 94.840 ;
        RECT 4.400 91.440 215.600 92.840 ;
        RECT 3.990 89.440 219.355 91.440 ;
        RECT 3.990 88.040 215.600 89.440 ;
        RECT 3.990 86.040 219.355 88.040 ;
        RECT 4.400 84.640 219.355 86.040 ;
        RECT 3.990 82.640 219.355 84.640 ;
        RECT 4.400 81.240 215.600 82.640 ;
        RECT 3.990 79.240 219.355 81.240 ;
        RECT 4.400 77.840 215.600 79.240 ;
        RECT 3.990 72.440 219.355 77.840 ;
        RECT 4.400 71.040 215.600 72.440 ;
        RECT 3.990 69.040 219.355 71.040 ;
        RECT 4.400 67.640 215.600 69.040 ;
        RECT 3.990 62.240 219.355 67.640 ;
        RECT 4.400 60.840 215.600 62.240 ;
        RECT 3.990 58.840 219.355 60.840 ;
        RECT 4.400 57.440 215.600 58.840 ;
        RECT 3.990 55.440 219.355 57.440 ;
        RECT 3.990 54.040 215.600 55.440 ;
        RECT 3.990 52.040 219.355 54.040 ;
        RECT 4.400 50.640 219.355 52.040 ;
        RECT 3.990 48.640 219.355 50.640 ;
        RECT 4.400 47.240 215.600 48.640 ;
        RECT 3.990 45.240 219.355 47.240 ;
        RECT 3.990 43.840 215.600 45.240 ;
        RECT 3.990 41.840 219.355 43.840 ;
        RECT 4.400 40.440 219.355 41.840 ;
        RECT 3.990 38.440 219.355 40.440 ;
        RECT 4.400 37.040 215.600 38.440 ;
        RECT 3.990 35.040 219.355 37.040 ;
        RECT 4.400 33.640 215.600 35.040 ;
        RECT 3.990 28.240 219.355 33.640 ;
        RECT 4.400 26.840 215.600 28.240 ;
        RECT 3.990 24.840 219.355 26.840 ;
        RECT 4.400 23.440 215.600 24.840 ;
        RECT 3.990 18.040 219.355 23.440 ;
        RECT 4.400 16.640 215.600 18.040 ;
        RECT 3.990 14.640 219.355 16.640 ;
        RECT 4.400 13.240 215.600 14.640 ;
        RECT 3.990 11.240 219.355 13.240 ;
        RECT 3.990 9.840 215.600 11.240 ;
        RECT 3.990 7.840 219.355 9.840 ;
        RECT 4.400 6.440 219.355 7.840 ;
        RECT 3.990 4.440 219.355 6.440 ;
        RECT 4.400 3.575 215.600 4.440 ;
      LAYER met4 ;
        RECT 61.015 102.855 139.545 145.345 ;
  END
END gpio_axi
END LIBRARY

